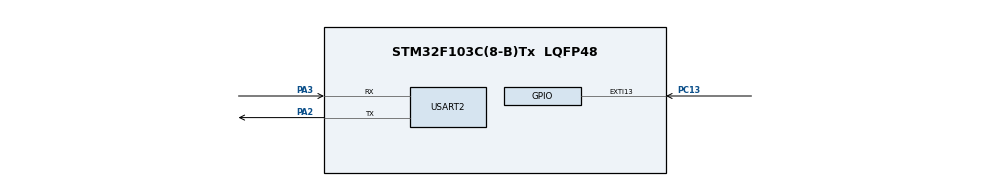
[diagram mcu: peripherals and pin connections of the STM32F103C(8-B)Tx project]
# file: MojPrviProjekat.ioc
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Mcu.Family=STM32F1
Mcu.Name=STM32F103C(8-B)Tx
Mcu.Package=LQFP48
NVIC.PriorityGroup=NVIC_PRIORITYGROUP_4
NVIC.USART2_IRQn=true\:0\:0\:false\:false\:true\:true\:true\:true
PA13.Mode=Serial_Wire
PA13.Signal=SYS_JTMS-SWDIO
PA14.Mode=Serial_Wire
PA14.Signal=SYS_JTCK-SWCLK
PA2.Mode=Asynchronous
PA2.Signal=USART2_TX
PA3.Mode=Asynchronous
PA3.Signal=USART2_RX
PC13-TAMPER-RTC.Signal=GPXTI13
ProjectManager.HeapSize=0x200
ProjectManager.StackSize=0x400
ProjectManager.TargetToolchain=MDK-ARM V5.32
RCC.AHBFreq_Value=64000000
RCC.APB1CLKDivider=RCC_HCLK_DIV2
RCC.APB1Freq_Value=32000000
RCC.APB1TimFreq_Value=64000000
RCC.APB2Freq_Value=64000000
RCC.APB2TimFreq_Value=64000000
RCC.HCLKFreq_Value=64000000
RCC.PLLMUL=RCC_PLL_MUL16
RCC.SYSCLKFreq_VALUE=64000000
RCC.SYSCLKSource=RCC_SYSCLKSOURCE_PLLCLK
RCC.USBFreq_Value=64000000
USART2.VirtualMode=VM_ASYNC
VP_TIM2_VS_ClockSourceINT.Mode=Internal
board=custom

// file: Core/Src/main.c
/* USER CODE BEGIN Header */
/**
  ******************************************************************************
  * @file           : main.c
  * @brief          : Main program body
  ******************************************************************************
  * @attention
  *
  * Copyright (c) 2024 STMicroelectronics.
  * All rights reserved.
  *
  * This software is licensed under terms that can be found in the LICENSE file
  * in the root directory of this software component.
  * If no LICENSE file comes with this software, it is provided AS-IS.
  *
  ******************************************************************************
  */
/* USER CODE END Header */
#include "main.h"

TIM_HandleTypeDef htim2;

UART_HandleTypeDef huart2;

void SystemClock_Config(void);
static void MX_GPIO_Init(void);
static void MX_TIM2_Init(void);
static void MX_USART2_UART_Init(void);

int main(void)
{

  /* MCU Configuration--------------------------------------------------------*/

  /* Reset of all peripherals, Initializes the Flash interface and the Systick. */
  HAL_Init();

  /* Configure the system clock */
  SystemClock_Config();

  /* Initialize all configured peripherals */
  MX_GPIO_Init();
  MX_TIM2_Init();
  MX_USART2_UART_Init();

  /* Infinite loop */
  while (1)
  {

  }
}

void SystemClock_Config(void)
{
  RCC_OscInitTypeDef RCC_OscInitStruct = {0};
  RCC_ClkInitTypeDef RCC_ClkInitStruct = {0};

  /** Initializes the RCC Oscillators according to the specified parameters
  * in the RCC_OscInitTypeDef structure.
  */
  RCC_OscInitStruct.OscillatorType = RCC_OSCILLATORTYPE_HSI;
  RCC_OscInitStruct.HSIState = RCC_HSI_ON;
  RCC_OscInitStruct.HSICalibrationValue = RCC_HSICALIBRATION_DEFAULT;
  RCC_OscInitStruct.PLL.PLLState = RCC_PLL_ON;
  RCC_OscInitStruct.PLL.PLLSource = RCC_PLLSOURCE_HSI_DIV2;
  RCC_OscInitStruct.PLL.PLLMUL = RCC_PLL_MUL6;
  if (HAL_RCC_OscConfig(&RCC_OscInitStruct) != HAL_OK)
  {
    Error_Handler();
  }

  /** Initializes the CPU, AHB and APB buses clocks
  */
  RCC_ClkInitStruct.ClockType = RCC_CLOCKTYPE_HCLK|RCC_CLOCKTYPE_SYSCLK
                              |RCC_CLOCKTYPE_PCLK1|RCC_CLOCKTYPE_PCLK2;
  RCC_ClkInitStruct.SYSCLKSource = RCC_SYSCLKSOURCE_PLLCLK;
  RCC_ClkInitStruct.AHBCLKDivider = RCC_SYSCLK_DIV1;
  RCC_ClkInitStruct.APB1CLKDivider = RCC_HCLK_DIV1;
  RCC_ClkInitStruct.APB2CLKDivider = RCC_HCLK_DIV1;

  if (HAL_RCC_ClockConfig(&RCC_ClkInitStruct, FLASH_LATENCY_0) != HAL_OK)
  {
    Error_Handler();
  }
}

static void MX_TIM2_Init(void)
{

  TIM_ClockConfigTypeDef sClockSourceConfig = {0};
  TIM_MasterConfigTypeDef sMasterConfig = {0};

  htim2.Instance = TIM2;
  htim2.Init.Prescaler = 0;
  htim2.Init.CounterMode = TIM_COUNTERMODE_UP;
  htim2.Init.Period = 65535;
  htim2.Init.ClockDivision = TIM_CLOCKDIVISION_DIV1;
  htim2.Init.AutoReloadPreload = TIM_AUTORELOAD_PRELOAD_DISABLE;
  if (HAL_TIM_Base_Init(&htim2) != HAL_OK)
  {
    Error_Handler();
  }
  sClockSourceConfig.ClockSource = TIM_CLOCKSOURCE_INTERNAL;
  if (HAL_TIM_ConfigClockSource(&htim2, &sClockSourceConfig) != HAL_OK)
  {
    Error_Handler();
  }
  sMasterConfig.MasterOutputTrigger = TIM_TRGO_RESET;
  sMasterConfig.MasterSlaveMode = TIM_MASTERSLAVEMODE_DISABLE;
  if (HAL_TIMEx_MasterConfigSynchronization(&htim2, &sMasterConfig) != HAL_OK)
  {
    Error_Handler();
  }

}

static void MX_USART2_UART_Init(void)
{

  huart2.Instance = USART2;
  huart2.Init.BaudRate = 115200;
  huart2.Init.WordLength = UART_WORDLENGTH_8B;
  huart2.Init.StopBits = UART_STOPBITS_1;
  huart2.Init.Parity = UART_PARITY_NONE;
  huart2.Init.Mode = UART_MODE_TX_RX;
  huart2.Init.HwFlowCtl = UART_HWCONTROL_NONE;
  huart2.Init.OverSampling = UART_OVERSAMPLING_16;
  if (HAL_UART_Init(&huart2) != HAL_OK)
  {
    Error_Handler();
  }

}

static void MX_GPIO_Init(void)
{

  /* GPIO Ports Clock Enable */
  __HAL_RCC_GPIOA_CLK_ENABLE();

}

void Error_Handler(void)
{
  __disable_irq();
  while (1)
  {
  }
}
